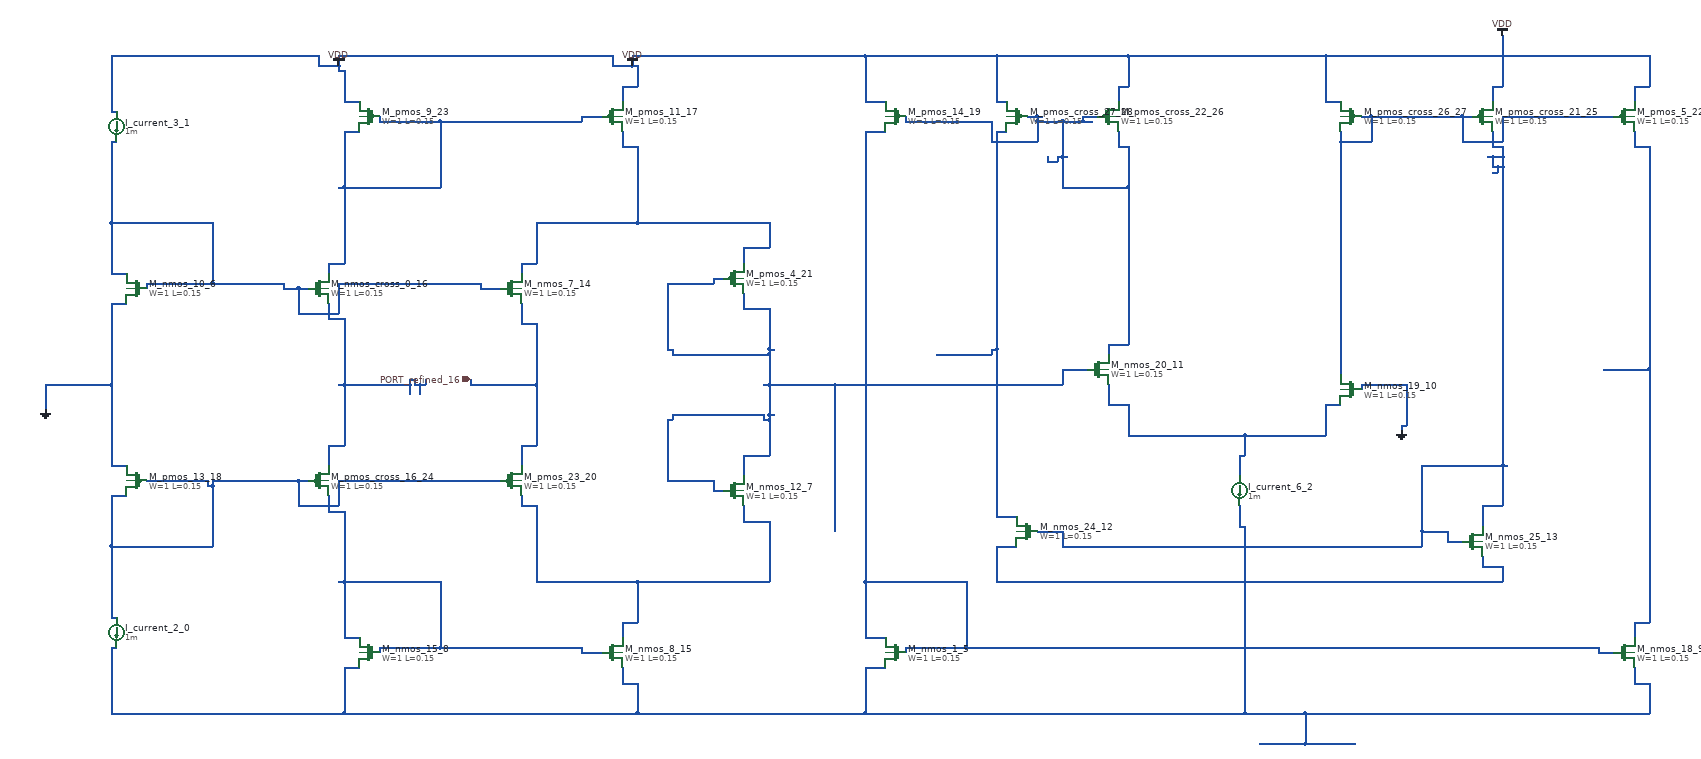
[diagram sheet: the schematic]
v {xschem version=3.4.8 file_version=1.2}
G {}
K {}
V {}
S {}
E {}
C {devices/isource.sym} 220 1280 0 0 {name="I_current_2_0" value=1m}
C {devices/isource.sym} 220 280 0 0 {name="I_current_3_1" value=1m}
C {devices/isource.sym} 2440 1000 0 0 {name="I_current_6_2" value=1m}
C {devices/gnd.sym} 2760 880 0 0 {name="l_gnd_17_3" lab="GND"}
C {devices/gnd.sym} 80 840 0 0 {name="l_gnd_28_4" lab="GND"}
C {sky130_fd_pr/nfet3_01v8.sym} 1760 1320 0 1 {name="M_nmos_1_5"
W=1
L=0.15
body=GND
nf=1
mult=1
ad="expr('int((@nf + 1)/2) * @W / @nf * 0.29')"
pd="expr('2*int((@nf + 1)/2) * (@W / @nf + 0.29)')"
as="expr('int((@nf + 2)/2) * @W / @nf * 0.29')"
ps="expr('2*int((@nf + 2)/2) * (@W / @nf + 0.29)')"
nrd="expr('0.29 / @W ')" nrs="expr('0.29 / @W ')"
sa=0 sb=0 sd=0
model=nfet_01v8
spiceprefix=X
}
C {sky130_fd_pr/nfet3_01v8.sym} 260 600 0 1 {name="M_nmos_10_6"
W=1
L=0.15
body=GND
nf=1
mult=1
ad="expr('int((@nf + 1)/2) * @W / @nf * 0.29')"
pd="expr('2*int((@nf + 1)/2) * (@W / @nf + 0.29)')"
as="expr('int((@nf + 2)/2) * @W / @nf * 0.29')"
ps="expr('2*int((@nf + 2)/2) * (@W / @nf + 0.29)')"
nrd="expr('0.29 / @W ')" nrs="expr('0.29 / @W ')"
sa=0 sb=0 sd=0
model=nfet_01v8
spiceprefix=X
}
C {sky130_fd_pr/nfet3_01v8.sym} 1440 1000 0 0 {name="M_nmos_12_7"
W=1
L=0.15
body=GND
nf=1
mult=1
ad="expr('int((@nf + 1)/2) * @W / @nf * 0.29')"
pd="expr('2*int((@nf + 1)/2) * (@W / @nf + 0.29)')"
as="expr('int((@nf + 2)/2) * @W / @nf * 0.29')"
ps="expr('2*int((@nf + 2)/2) * (@W / @nf + 0.29)')"
nrd="expr('0.29 / @W ')" nrs="expr('0.29 / @W ')"
sa=0 sb=0 sd=0
model=nfet_01v8
spiceprefix=X
}
C {sky130_fd_pr/nfet3_01v8.sym} 720 1320 0 1 {name="M_nmos_15_8"
W=1
L=0.15
body=GND
nf=1
mult=1
ad="expr('int((@nf + 1)/2) * @W / @nf * 0.29')"
pd="expr('2*int((@nf + 1)/2) * (@W / @nf + 0.29)')"
as="expr('int((@nf + 2)/2) * @W / @nf * 0.29')"
ps="expr('2*int((@nf + 2)/2) * (@W / @nf + 0.29)')"
nrd="expr('0.29 / @W ')" nrs="expr('0.29 / @W ')"
sa=0 sb=0 sd=0
model=nfet_01v8
spiceprefix=X
}
C {sky130_fd_pr/nfet3_01v8.sym} 3200 1320 0 0 {name="M_nmos_18_9"
W=1
L=0.15
body=GND
nf=1
mult=1
ad="expr('int((@nf + 1)/2) * @W / @nf * 0.29')"
pd="expr('2*int((@nf + 1)/2) * (@W / @nf + 0.29)')"
as="expr('int((@nf + 2)/2) * @W / @nf * 0.29')"
ps="expr('2*int((@nf + 2)/2) * (@W / @nf + 0.29)')"
nrd="expr('0.29 / @W ')" nrs="expr('0.29 / @W ')"
sa=0 sb=0 sd=0
model=nfet_01v8
spiceprefix=X
}
C {sky130_fd_pr/nfet3_01v8.sym} 2660 800 0 1 {name="M_nmos_19_10"
W=1
L=0.15
body=GND
nf=1
mult=1
ad="expr('int((@nf + 1)/2) * @W / @nf * 0.29')"
pd="expr('2*int((@nf + 1)/2) * (@W / @nf + 0.29)')"
as="expr('int((@nf + 2)/2) * @W / @nf * 0.29')"
ps="expr('2*int((@nf + 2)/2) * (@W / @nf + 0.29)')"
nrd="expr('0.29 / @W ')" nrs="expr('0.29 / @W ')"
sa=0 sb=0 sd=0
model=nfet_01v8
spiceprefix=X
}
C {sky130_fd_pr/nfet3_01v8.sym} 2160 760 0 0 {name="M_nmos_20_11"
W=1
L=0.15
body=GND
nf=1
mult=1
ad="expr('int((@nf + 1)/2) * @W / @nf * 0.29')"
pd="expr('2*int((@nf + 1)/2) * (@W / @nf + 0.29)')"
as="expr('int((@nf + 2)/2) * @W / @nf * 0.29')"
ps="expr('2*int((@nf + 2)/2) * (@W / @nf + 0.29)')"
nrd="expr('0.29 / @W ')" nrs="expr('0.29 / @W ')"
sa=0 sb=0 sd=0
model=nfet_01v8
spiceprefix=X
}
C {sky130_fd_pr/nfet3_01v8.sym} 2020 1080 0 1 {name="M_nmos_24_12"
W=1
L=0.15
body=GND
nf=1
mult=1
ad="expr('int((@nf + 1)/2) * @W / @nf * 0.29')"
pd="expr('2*int((@nf + 1)/2) * (@W / @nf + 0.29)')"
as="expr('int((@nf + 2)/2) * @W / @nf * 0.29')"
ps="expr('2*int((@nf + 2)/2) * (@W / @nf + 0.29)')"
nrd="expr('0.29 / @W ')" nrs="expr('0.29 / @W ')"
sa=0 sb=0 sd=0
model=nfet_01v8
spiceprefix=X
}
C {sky130_fd_pr/nfet3_01v8.sym} 2900 1100 0 0 {name="M_nmos_25_13"
W=1
L=0.15
body=GND
nf=1
mult=1
ad="expr('int((@nf + 1)/2) * @W / @nf * 0.29')"
pd="expr('2*int((@nf + 1)/2) * (@W / @nf + 0.29)')"
as="expr('int((@nf + 2)/2) * @W / @nf * 0.29')"
ps="expr('2*int((@nf + 2)/2) * (@W / @nf + 0.29)')"
nrd="expr('0.29 / @W ')" nrs="expr('0.29 / @W ')"
sa=0 sb=0 sd=0
model=nfet_01v8
spiceprefix=X
}
C {sky130_fd_pr/nfet3_01v8.sym} 1000 600 0 0 {name="M_nmos_7_14"
W=1
L=0.15
body=GND
nf=1
mult=1
ad="expr('int((@nf + 1)/2) * @W / @nf * 0.29')"
pd="expr('2*int((@nf + 1)/2) * (@W / @nf + 0.29)')"
as="expr('int((@nf + 2)/2) * @W / @nf * 0.29')"
ps="expr('2*int((@nf + 2)/2) * (@W / @nf + 0.29)')"
nrd="expr('0.29 / @W ')" nrs="expr('0.29 / @W ')"
sa=0 sb=0 sd=0
model=nfet_01v8
spiceprefix=X
}
C {sky130_fd_pr/nfet3_01v8.sym} 1200 1320 0 0 {name="M_nmos_8_15"
W=1
L=0.15
body=GND
nf=1
mult=1
ad="expr('int((@nf + 1)/2) * @W / @nf * 0.29')"
pd="expr('2*int((@nf + 1)/2) * (@W / @nf + 0.29)')"
as="expr('int((@nf + 2)/2) * @W / @nf * 0.29')"
ps="expr('2*int((@nf + 2)/2) * (@W / @nf + 0.29)')"
nrd="expr('0.29 / @W ')" nrs="expr('0.29 / @W ')"
sa=0 sb=0 sd=0
model=nfet_01v8
spiceprefix=X
}
C {sky130_fd_pr/nfet3_01v8.sym} 620 600 0 0 {name="M_nmos_cross_0_16"
W=1
L=0.15
body=GND
nf=1
mult=1
ad="expr('int((@nf + 1)/2) * @W / @nf * 0.29')"
pd="expr('2*int((@nf + 1)/2) * (@W / @nf + 0.29)')"
as="expr('int((@nf + 2)/2) * @W / @nf * 0.29')"
ps="expr('2*int((@nf + 2)/2) * (@W / @nf + 0.29)')"
nrd="expr('0.29 / @W ')" nrs="expr('0.29 / @W ')"
sa=0 sb=0 sd=0
model=nfet_01v8
spiceprefix=X
}
C {sky130_fd_pr/pfet3_01v8.sym} 1200 260 0 0 {name="M_pmos_11_17"
W=1
L=0.15
body=VDD
nf=1
mult=1
ad="expr('int((@nf + 1)/2) * @W / @nf * 0.29')"
pd="expr('2*int((@nf + 1)/2) * (@W / @nf + 0.29)')"
as="expr('int((@nf + 2)/2) * @W / @nf * 0.29')"
ps="expr('2*int((@nf + 2)/2) * (@W / @nf + 0.29)')"
nrd="expr('0.29 / @W ')" nrs="expr('0.29 / @W ')"
sa=0 sb=0 sd=0
model=pfet_01v8
spiceprefix=X
}
C {sky130_fd_pr/pfet3_01v8.sym} 260 980 0 1 {name="M_pmos_13_18"
W=1
L=0.15
body=VDD
nf=1
mult=1
ad="expr('int((@nf + 1)/2) * @W / @nf * 0.29')"
pd="expr('2*int((@nf + 1)/2) * (@W / @nf + 0.29)')"
as="expr('int((@nf + 2)/2) * @W / @nf * 0.29')"
ps="expr('2*int((@nf + 2)/2) * (@W / @nf + 0.29)')"
nrd="expr('0.29 / @W ')" nrs="expr('0.29 / @W ')"
sa=0 sb=0 sd=0
model=pfet_01v8
spiceprefix=X
}
C {sky130_fd_pr/pfet3_01v8.sym} 1760 260 0 1 {name="M_pmos_14_19"
W=1
L=0.15
body=VDD
nf=1
mult=1
ad="expr('int((@nf + 1)/2) * @W / @nf * 0.29')"
pd="expr('2*int((@nf + 1)/2) * (@W / @nf + 0.29)')"
as="expr('int((@nf + 2)/2) * @W / @nf * 0.29')"
ps="expr('2*int((@nf + 2)/2) * (@W / @nf + 0.29)')"
nrd="expr('0.29 / @W ')" nrs="expr('0.29 / @W ')"
sa=0 sb=0 sd=0
model=pfet_01v8
spiceprefix=X
}
C {sky130_fd_pr/pfet3_01v8.sym} 1000 980 0 0 {name="M_pmos_23_20"
W=1
L=0.15
body=VDD
nf=1
mult=1
ad="expr('int((@nf + 1)/2) * @W / @nf * 0.29')"
pd="expr('2*int((@nf + 1)/2) * (@W / @nf + 0.29)')"
as="expr('int((@nf + 2)/2) * @W / @nf * 0.29')"
ps="expr('2*int((@nf + 2)/2) * (@W / @nf + 0.29)')"
nrd="expr('0.29 / @W ')" nrs="expr('0.29 / @W ')"
sa=0 sb=0 sd=0
model=pfet_01v8
spiceprefix=X
}
C {sky130_fd_pr/pfet3_01v8.sym} 1440 580 0 0 {name="M_pmos_4_21"
W=1
L=0.15
body=VDD
nf=1
mult=1
ad="expr('int((@nf + 1)/2) * @W / @nf * 0.29')"
pd="expr('2*int((@nf + 1)/2) * (@W / @nf + 0.29)')"
as="expr('int((@nf + 2)/2) * @W / @nf * 0.29')"
ps="expr('2*int((@nf + 2)/2) * (@W / @nf + 0.29)')"
nrd="expr('0.29 / @W ')" nrs="expr('0.29 / @W ')"
sa=0 sb=0 sd=0
model=pfet_01v8
spiceprefix=X
}
C {sky130_fd_pr/pfet3_01v8.sym} 3200 260 0 0 {name="M_pmos_5_22"
W=1
L=0.15
body=VDD
nf=1
mult=1
ad="expr('int((@nf + 1)/2) * @W / @nf * 0.29')"
pd="expr('2*int((@nf + 1)/2) * (@W / @nf + 0.29)')"
as="expr('int((@nf + 2)/2) * @W / @nf * 0.29')"
ps="expr('2*int((@nf + 2)/2) * (@W / @nf + 0.29)')"
nrd="expr('0.29 / @W ')" nrs="expr('0.29 / @W ')"
sa=0 sb=0 sd=0
model=pfet_01v8
spiceprefix=X
}
C {sky130_fd_pr/pfet3_01v8.sym} 720 260 0 1 {name="M_pmos_9_23"
W=1
L=0.15
body=VDD
nf=1
mult=1
ad="expr('int((@nf + 1)/2) * @W / @nf * 0.29')"
pd="expr('2*int((@nf + 1)/2) * (@W / @nf + 0.29)')"
as="expr('int((@nf + 2)/2) * @W / @nf * 0.29')"
ps="expr('2*int((@nf + 2)/2) * (@W / @nf + 0.29)')"
nrd="expr('0.29 / @W ')" nrs="expr('0.29 / @W ')"
sa=0 sb=0 sd=0
model=pfet_01v8
spiceprefix=X
}
C {sky130_fd_pr/pfet3_01v8.sym} 620 980 0 0 {name="M_pmos_cross_16_24"
W=1
L=0.15
body=VDD
nf=1
mult=1
ad="expr('int((@nf + 1)/2) * @W / @nf * 0.29')"
pd="expr('2*int((@nf + 1)/2) * (@W / @nf + 0.29)')"
as="expr('int((@nf + 2)/2) * @W / @nf * 0.29')"
ps="expr('2*int((@nf + 2)/2) * (@W / @nf + 0.29)')"
nrd="expr('0.29 / @W ')" nrs="expr('0.29 / @W ')"
sa=0 sb=0 sd=0
model=pfet_01v8
spiceprefix=X
}
C {sky130_fd_pr/pfet3_01v8.sym} 2920 260 0 0 {name="M_pmos_cross_21_25"
W=1
L=0.15
body=VDD
nf=1
mult=1
ad="expr('int((@nf + 1)/2) * @W / @nf * 0.29')"
pd="expr('2*int((@nf + 1)/2) * (@W / @nf + 0.29)')"
as="expr('int((@nf + 2)/2) * @W / @nf * 0.29')"
ps="expr('2*int((@nf + 2)/2) * (@W / @nf + 0.29)')"
nrd="expr('0.29 / @W ')" nrs="expr('0.29 / @W ')"
sa=0 sb=0 sd=0
model=pfet_01v8
spiceprefix=X
}
C {sky130_fd_pr/pfet3_01v8.sym} 2180 260 0 0 {name="M_pmos_cross_22_26"
W=1
L=0.15
body=VDD
nf=1
mult=1
ad="expr('int((@nf + 1)/2) * @W / @nf * 0.29')"
pd="expr('2*int((@nf + 1)/2) * (@W / @nf + 0.29)')"
as="expr('int((@nf + 2)/2) * @W / @nf * 0.29')"
ps="expr('2*int((@nf + 2)/2) * (@W / @nf + 0.29)')"
nrd="expr('0.29 / @W ')" nrs="expr('0.29 / @W ')"
sa=0 sb=0 sd=0
model=pfet_01v8
spiceprefix=X
}
C {sky130_fd_pr/pfet3_01v8.sym} 2660 260 0 1 {name="M_pmos_cross_26_27"
W=1
L=0.15
body=VDD
nf=1
mult=1
ad="expr('int((@nf + 1)/2) * @W / @nf * 0.29')"
pd="expr('2*int((@nf + 1)/2) * (@W / @nf + 0.29)')"
as="expr('int((@nf + 2)/2) * @W / @nf * 0.29')"
ps="expr('2*int((@nf + 2)/2) * (@W / @nf + 0.29)')"
nrd="expr('0.29 / @W ')" nrs="expr('0.29 / @W ')"
sa=0 sb=0 sd=0
model=pfet_01v8
spiceprefix=X
}
C {sky130_fd_pr/pfet3_01v8.sym} 2000 260 0 1 {name="M_pmos_cross_27_28"
W=1
L=0.15
body=VDD
nf=1
mult=1
ad="expr('int((@nf + 1)/2) * @W / @nf * 0.29')"
pd="expr('2*int((@nf + 1)/2) * (@W / @nf + 0.29)')"
as="expr('int((@nf + 2)/2) * @W / @nf * 0.29')"
ps="expr('2*int((@nf + 2)/2) * (@W / @nf + 0.29)')"
nrd="expr('0.29 / @W ')" nrs="expr('0.29 / @W ')"
sa=0 sb=0 sd=0
model=pfet_01v8
spiceprefix=X
}
C {devices/ipin.sym} 920 780 0 0 {name="p_port_31_29" lab="PORT_refined_16"}
C {devices/vdd.sym} 2960 100 0 0 {name="l_vdd_29_30" lab="VDD"}
C {devices/vdd.sym} 660 160 0 0 {name="l_vdd_30_31" lab="VDD"}
C {devices/vdd.sym} 1240 160 0 0 {name="l_vdd_32_32" lab="VDD"}
N 2480 1500 2570 1500 {}
N 2570 1500 2670 1500 {}
N 210 1440 670 1440 {}
N 670 1440 1250 1440 {}
N 1250 1440 1700 1440 {}
N 1700 1440 2450 1440 {}
N 2450 1440 2570 1440 {}
N 2570 1440 3250 1440 {}
N 1220 1380 1250 1380 {}
N 3220 1380 3250 1380 {}
N 670 1350 700 1350 {}
N 1700 1350 1740 1350 {}
N 210 1310 220 1310 {}
N 1960 1180 2450 1180 {}
N 2450 1180 2960 1180 {}
N 2920 1150 2960 1150 {}
N 1960 1110 2000 1110 {}
N 2440 1070 2450 1070 {}
N 210 1440 210 1310 {}
N 670 1440 670 1350 {}
N 1220 1380 1220 1350 {}
N 1250 1440 1250 1380 {}
N 1700 1440 1700 1350 {}
N 1960 1180 1960 1110 {}
N 2440 1070 2440 1030 {}
N 2450 1440 2450 1180 {}
N 2450 1180 2450 1070 {}
N 2570 1500 2570 1440 {}
N 2920 1150 2920 1130 {}
N 2960 1180 2960 1150 {}
N 3220 1380 3220 1350 {}
N 3250 1440 3250 1380 {}
N 210 1250 220 1250 {}
N 210 1110 410 1110 {}
N 580 1030 660 1030 {}
N 210 1010 240 1010 {}
N 400 990 410 990 {}
N 280 980 400 980 {}
N 410 980 580 980 {}
N 580 980 600 980 {}
N 660 980 980 980 {}
N 210 1250 210 1110 {}
N 210 1110 210 1010 {}
N 400 990 400 980 {}
N 410 1110 410 990 {}
N 410 990 410 980 {}
N 580 1030 580 980 {}
N 660 1030 660 980 {}
N 2640 310 2700 310 {}
N 2880 310 2960 310 {}
N 2680 260 2700 260 {}
N 2700 260 2880 260 {}
N 2880 260 2900 260 {}
N 2960 260 3180 260 {}
N 2640 770 2640 310 {}
N 2640 310 2640 290 {}
N 2700 310 2700 260 {}
N 2880 310 2880 260 {}
N 2960 310 2960 260 {}
N 2180 710 2220 710 {}
N 2090 400 2220 400 {}
N 2060 350 2080 350 {}
N 2080 340 2090 340 {}
N 2090 340 2100 340 {}
N 2200 320 2220 320 {}
N 1950 310 2040 310 {}
N 1780 270 1950 270 {}
N 2040 270 2090 270 {}
N 2090 270 2130 270 {}
N 2130 270 2150 270 {}
N 2020 260 2040 260 {}
N 2040 260 2050 260 {}
N 2130 260 2160 260 {}
N 1780 270 1780 260 {}
N 1950 310 1950 270 {}
N 2040 310 2040 270 {}
N 2040 270 2040 260 {}
N 2060 350 2060 340 {}
N 2080 350 2080 340 {}
N 2090 400 2090 340 {}
N 2090 340 2090 270 {}
N 2130 270 2130 260 {}
N 2180 730 2180 710 {}
N 2200 320 2200 290 {}
N 2220 710 2220 400 {}
N 2220 400 2220 320 {}
N 210 250 220 250 {}
N 670 230 700 230 {}
N 1700 230 1740 230 {}
N 1960 230 1980 230 {}
N 2610 230 2640 230 {}
N 1220 200 1250 200 {}
N 2200 200 2220 200 {}
N 2940 200 2960 200 {}
N 3220 200 3250 200 {}
N 660 170 670 170 {}
N 620 160 660 160 {}
N 1200 160 1240 160 {}
N 1240 160 1250 160 {}
N 210 140 620 140 {}
N 660 140 1200 140 {}
N 1240 140 1700 140 {}
N 1700 140 1960 140 {}
N 1960 140 2220 140 {}
N 2220 140 2610 140 {}
N 2610 140 2960 140 {}
N 2960 140 3250 140 {}
N 210 250 210 140 {}
N 620 160 620 140 {}
N 660 170 660 160 {}
N 660 160 660 140 {}
N 670 230 670 170 {}
N 1200 160 1200 140 {}
N 1220 230 1220 200 {}
N 1240 160 1240 140 {}
N 1250 200 1250 160 {}
N 1700 230 1700 140 {}
N 1960 230 1960 140 {}
N 2200 230 2200 200 {}
N 2220 200 2220 140 {}
N 2610 230 2610 140 {}
N 2940 230 2940 200 {}
N 2960 200 2960 140 {}
N 2960 140 2960 100 {}
N 3220 230 3220 200 {}
N 3250 200 3250 140 {}
N 1960 1050 2000 1050 {}
N 1840 730 1950 730 {}
N 1950 720 1960 720 {}
N 1960 290 1980 290 {}
N 1950 730 1950 720 {}
N 1960 1050 1960 720 {}
N 1960 720 1960 290 {}
N 2090 1110 2800 1110 {}
N 2850 1100 2880 1100 {}
N 2040 1080 2090 1080 {}
N 2800 1080 2850 1080 {}
N 2920 1030 2960 1030 {}
N 2800 950 2960 950 {}
N 2960 950 2970 950 {}
N 2940 370 2950 370 {}
N 2940 360 2950 360 {}
N 2950 360 2960 360 {}
N 2930 340 2940 340 {}
N 2940 340 2960 340 {}
N 2940 320 2960 320 {}
N 2090 1110 2090 1080 {}
N 2800 1110 2800 1080 {}
N 2800 1080 2800 950 {}
N 2850 1100 2850 1080 {}
N 2920 1070 2920 1030 {}
N 2940 360 2940 340 {}
N 2940 320 2940 290 {}
N 2950 370 2950 360 {}
N 2960 1030 2960 950 {}
N 2960 950 2960 360 {}
N 2960 360 2960 340 {}
N 2960 340 2960 320 {}
N 1020 550 1050 550 {}
N 1460 520 1510 520 {}
N 1050 470 1250 470 {}
N 1250 470 1510 470 {}
N 1220 320 1250 320 {}
N 1020 570 1020 550 {}
N 1050 550 1050 470 {}
N 1220 320 1220 290 {}
N 1250 470 1250 320 {}
N 1460 550 1460 520 {}
N 1510 520 1510 470 {}
N 1020 910 1050 910 {}
N 920 790 1050 790 {}
N 1020 670 1050 670 {}
N 920 790 920 780 {}
N 1020 950 1020 910 {}
N 1020 670 1020 630 {}
N 1050 910 1050 790 {}
N 1050 790 1050 670 {}
N 640 550 670 550 {}
N 660 400 670 400 {}
N 670 400 860 400 {}
N 670 290 700 290 {}
N 740 270 860 270 {}
N 860 270 1140 270 {}
N 1140 260 1180 260 {}
N 640 570 640 550 {}
N 670 550 670 400 {}
N 670 400 670 290 {}
N 740 270 740 260 {}
N 860 400 860 270 {}
N 1140 270 1140 260 {}
N 640 910 670 910 {}
N 660 790 670 790 {}
N 670 790 800 790 {}
N 810 790 820 790 {}
N 820 790 830 790 {}
N 800 780 810 780 {}
N 640 660 670 660 {}
N 640 950 640 910 {}
N 640 660 640 630 {}
N 670 910 670 790 {}
N 670 790 670 660 {}
N 800 810 800 790 {}
N 800 790 800 780 {}
N 810 790 810 780 {}
N 820 810 820 790 {}
N 830 790 830 780 {}
N 3150 1320 3180 1320 {}
N 1780 1310 1900 1310 {}
N 1900 1310 3150 1310 {}
N 1700 1290 1740 1290 {}
N 1700 1180 1900 1180 {}
N 1700 290 1740 290 {}
N 1700 1290 1700 1180 {}
N 1700 1180 1700 290 {}
N 1780 1320 1780 1310 {}
N 1900 1310 1900 1180 {}
N 3150 1320 3150 1310 {}
N 210 950 240 950 {}
N 2760 870 2770 870 {}
N 80 790 210 790 {}
N 2680 790 2770 790 {}
N 210 630 240 630 {}
N 80 840 80 790 {}
N 210 950 210 790 {}
N 210 790 210 630 {}
N 2680 800 2680 790 {}
N 2760 880 2760 870 {}
N 2770 870 2770 790 {}
N 580 650 660 650 {}
N 550 600 580 600 {}
N 580 600 600 600 {}
N 940 600 980 600 {}
N 280 590 410 590 {}
N 410 590 550 590 {}
N 660 590 940 590 {}
N 210 570 240 570 {}
N 210 470 410 470 {}
N 210 310 220 310 {}
N 210 570 210 470 {}
N 210 470 210 310 {}
N 280 600 280 590 {}
N 410 590 410 470 {}
N 550 600 550 590 {}
N 580 650 580 600 {}
N 660 650 660 590 {}
N 940 600 940 590 {}
N 1400 1000 1420 1000 {}
N 1310 980 1400 980 {}
N 1460 930 1510 930 {}
N 1310 860 1320 860 {}
N 1500 860 1510 860 {}
N 1320 850 1500 850 {}
N 1510 850 1520 850 {}
N 1500 790 1510 790 {}
N 1510 790 1640 790 {}
N 1640 790 2090 790 {}
N 2090 760 2140 760 {}
N 1320 730 1510 730 {}
N 1310 720 1320 720 {}
N 1510 720 1520 720 {}
N 1460 640 1510 640 {}
N 1310 590 1400 590 {}
N 1400 580 1420 580 {}
N 1310 980 1310 860 {}
N 1310 720 1310 590 {}
N 1320 860 1320 850 {}
N 1320 730 1320 720 {}
N 1400 1000 1400 980 {}
N 1400 590 1400 580 {}
N 1460 970 1460 930 {}
N 1460 640 1460 610 {}
N 1500 860 1500 850 {}
N 1510 930 1510 860 {}
N 1510 860 1510 850 {}
N 1510 850 1510 790 {}
N 1510 790 1510 730 {}
N 1510 730 1510 720 {}
N 1510 720 1510 640 {}
N 1640 1080 1640 790 {}
N 2090 790 2090 760 {}
N 1220 1260 1250 1260 {}
N 1050 1180 1250 1180 {}
N 1250 1180 1510 1180 {}
N 1460 1060 1510 1060 {}
N 1020 1030 1050 1030 {}
N 1020 1030 1020 1010 {}
N 1050 1180 1050 1030 {}
N 1220 1290 1220 1260 {}
N 1250 1260 1250 1180 {}
N 1460 1060 1460 1030 {}
N 1510 1180 1510 1060 {}
N 1140 1320 1180 1320 {}
N 740 1310 860 1310 {}
N 860 1310 1140 1310 {}
N 670 1290 700 1290 {}
N 660 1180 670 1180 {}
N 670 1180 860 1180 {}
N 640 1040 670 1040 {}
N 640 1040 640 1010 {}
N 670 1290 670 1180 {}
N 670 1180 670 1040 {}
N 740 1320 740 1310 {}
N 860 1310 860 1180 {}
N 1140 1320 1140 1310 {}
N 3220 1260 3250 1260 {}
N 3160 760 3250 760 {}
N 3220 320 3250 320 {}
N 3220 1290 3220 1260 {}
N 3220 320 3220 290 {}
N 3250 1260 3250 760 {}
N 3250 760 3250 320 {}
N 2440 930 2450 930 {}
N 2220 890 2450 890 {}
N 2450 890 2610 890 {}
N 2180 830 2220 830 {}
N 2610 830 2640 830 {}
N 2180 830 2180 790 {}
N 2220 890 2220 830 {}
N 2440 970 2440 930 {}
N 2450 930 2450 890 {}
N 2610 890 2610 830 {}
